VERSION 5.7 ;
  NOWIREEXTENSIONATPIN ON ;
  DIVIDERCHAR "/" ;
  BUSBITCHARS "[]" ;
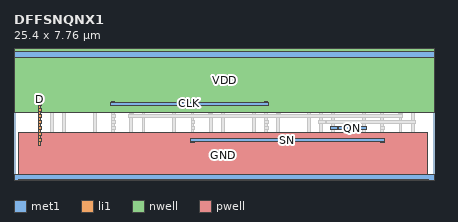
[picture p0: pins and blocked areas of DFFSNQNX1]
MACRO DFFSNQNX1
  CLASS CORE ;
  FOREIGN DFFSNQNX1 ;
  ORIGIN 0.000 0.000 ;
  SIZE 25.400 BY 7.760 ;
  SYMMETRY X Y ;
  SITE unitrh ;
  PIN QN
    DIRECTION OUTPUT ;
    USE SIGNAL ;
    ANTENNAGATEAREA 1.033250 ;
    PORT
      LAYER met1 ;
        RECT 21.040 3.225 21.270 3.255 ;
        RECT 19.625 3.055 21.300 3.225 ;
        RECT 21.040 3.025 21.270 3.055 ;
    END
    PORT
      LAYER met1 ;
        RECT 19.190 3.225 19.420 3.255 ;
        RECT 19.160 3.055 19.570 3.225 ;
        RECT 19.190 3.025 19.420 3.055 ;
    END
  END QN
  PIN D
    DIRECTION INPUT ;
    USE SIGNAL ;
    ANTENNAGATEAREA 1.033250 ;
    PORT
      LAYER li1 ;
        RECT 1.460 4.705 1.630 5.045 ;
        RECT 1.460 4.535 1.685 4.705 ;
        RECT 1.460 4.335 1.630 4.535 ;
        RECT 1.460 4.165 1.685 4.335 ;
        RECT 1.460 3.965 1.630 4.165 ;
        RECT 1.460 3.795 1.685 3.965 ;
        RECT 1.460 3.595 1.630 3.795 ;
        RECT 1.460 3.425 1.685 3.595 ;
        RECT 1.460 3.225 1.630 3.425 ;
        RECT 1.460 3.055 1.685 3.225 ;
        RECT 1.460 2.855 1.630 3.055 ;
        RECT 1.460 2.685 1.685 2.855 ;
        RECT 1.460 2.485 1.630 2.685 ;
        RECT 1.460 2.315 1.685 2.485 ;
        RECT 1.460 2.095 1.630 2.315 ;
    END
  END D
  PIN CLK
    DIRECTION INPUT ;
    USE SIGNAL ;
    ANTENNAGATEAREA 2.042100 ;
    PORT
      LAYER met1 ;
        RECT 5.870 4.705 6.100 4.735 ;
        RECT 15.120 4.705 15.350 4.735 ;
        RECT 5.840 4.535 15.380 4.705 ;
        RECT 5.870 4.505 6.100 4.535 ;
        RECT 15.120 4.505 15.350 4.535 ;
    END
  END CLK
  PIN SN
    DIRECTION INPUT ;
    USE SIGNAL ;
    ANTENNAGATEAREA 2.029700 ;
    PORT
      LAYER met1 ;
        RECT 10.680 2.485 10.910 2.515 ;
        RECT 22.150 2.485 22.380 2.515 ;
        RECT 10.650 2.315 22.410 2.485 ;
        RECT 10.680 2.285 10.910 2.315 ;
        RECT 22.150 2.285 22.380 2.315 ;
    END
  END SN
  PIN VDD
    DIRECTION INOUT ;
    USE POWER ;
    SHAPE ABUTMENT ;
    PORT
      LAYER nwell ;
        RECT 0.000 4.110 25.400 7.940 ;
      LAYER met1 ;
        RECT 0.000 7.410 25.400 7.760 ;
    END
  END VDD
  PIN GND
    DIRECTION INOUT ;
    USE GROUND ;
    SHAPE ABUTMENT ;
    PORT
      LAYER pwell ;
        RECT 0.265 0.060 25.025 2.900 ;
        RECT 0.265 0.010 25.080 0.060 ;
        RECT 0.320 0.000 25.080 0.010 ;
      LAYER met1 ;
        RECT 0.000 0.000 25.400 0.350 ;
    END
  END GND
  OBS
      LAYER li1 ;
        RECT 0.000 7.410 25.400 7.760 ;
        RECT 0.265 4.290 0.605 7.410 ;
        RECT 1.140 5.315 1.310 7.410 ;
        RECT 1.580 5.465 1.750 7.200 ;
        RECT 2.020 5.735 2.190 7.410 ;
        RECT 2.460 5.465 2.630 7.200 ;
        RECT 2.900 5.735 3.070 7.410 ;
        RECT 1.580 5.295 3.110 5.465 ;
        RECT 2.230 4.890 2.400 5.045 ;
        RECT 2.200 4.715 2.400 4.890 ;
        RECT 0.265 0.350 0.605 2.900 ;
        RECT 2.200 2.095 2.370 4.715 ;
        RECT 1.045 1.845 1.215 1.925 ;
        RECT 2.015 1.845 2.185 1.925 ;
        RECT 2.940 1.920 3.110 5.295 ;
        RECT 3.595 4.290 3.935 7.410 ;
        RECT 4.770 5.395 4.940 7.410 ;
        RECT 5.210 5.420 5.380 7.200 ;
        RECT 5.650 5.735 5.820 7.410 ;
        RECT 6.090 5.420 6.260 7.200 ;
        RECT 6.530 5.735 6.700 7.410 ;
        RECT 6.970 5.420 7.140 7.200 ;
        RECT 7.410 5.735 7.580 7.410 ;
        RECT 5.210 5.250 7.920 5.420 ;
        RECT 1.045 1.675 2.185 1.845 ;
        RECT 1.045 0.545 1.215 1.675 ;
        RECT 1.530 0.350 1.700 1.300 ;
        RECT 2.015 0.795 2.185 1.675 ;
        RECT 2.500 1.750 3.110 1.920 ;
        RECT 2.500 1.015 2.670 1.750 ;
        RECT 2.985 0.795 3.155 1.565 ;
        RECT 2.015 0.625 3.155 0.795 ;
        RECT 2.015 0.545 2.185 0.625 ;
        RECT 2.985 0.545 3.155 0.625 ;
        RECT 3.595 0.350 3.935 2.900 ;
        RECT 4.790 2.095 4.960 5.045 ;
        RECT 5.900 4.705 6.070 5.045 ;
        RECT 5.900 4.535 6.125 4.705 ;
        RECT 5.900 3.965 6.070 4.535 ;
        RECT 5.900 3.795 6.125 3.965 ;
        RECT 5.900 3.595 6.070 3.795 ;
        RECT 5.900 3.425 6.125 3.595 ;
        RECT 5.900 3.225 6.070 3.425 ;
        RECT 5.900 3.055 6.125 3.225 ;
        RECT 5.900 2.095 6.070 3.055 ;
        RECT 7.010 2.095 7.180 5.045 ;
        RECT 7.750 4.415 7.920 5.250 ;
        RECT 7.745 4.085 7.920 4.415 ;
        RECT 8.405 4.290 8.745 7.410 ;
        RECT 9.580 5.395 9.750 7.410 ;
        RECT 10.020 5.420 10.190 7.200 ;
        RECT 10.460 5.735 10.630 7.410 ;
        RECT 10.900 5.420 11.070 7.200 ;
        RECT 11.340 5.735 11.510 7.410 ;
        RECT 11.780 5.420 11.950 7.200 ;
        RECT 12.220 5.735 12.390 7.410 ;
        RECT 10.020 5.250 12.730 5.420 ;
        RECT 4.270 1.855 4.440 1.935 ;
        RECT 5.240 1.855 5.410 1.935 ;
        RECT 6.210 1.855 6.380 1.935 ;
        RECT 4.270 1.685 6.380 1.855 ;
        RECT 4.270 0.555 4.440 1.685 ;
        RECT 4.755 0.350 4.925 1.310 ;
        RECT 5.240 0.805 5.410 1.685 ;
        RECT 6.210 1.605 6.380 1.685 ;
        RECT 5.730 1.260 5.900 1.340 ;
        RECT 6.780 1.260 6.950 1.935 ;
        RECT 7.750 1.930 7.920 4.085 ;
        RECT 5.730 1.090 6.950 1.260 ;
        RECT 5.730 1.010 5.900 1.090 ;
        RECT 6.210 0.805 6.380 0.885 ;
        RECT 5.240 0.635 6.380 0.805 ;
        RECT 5.240 0.555 5.410 0.635 ;
        RECT 6.210 0.555 6.380 0.635 ;
        RECT 6.780 0.805 6.950 1.090 ;
        RECT 7.265 1.760 7.920 1.930 ;
        RECT 7.265 1.025 7.435 1.760 ;
        RECT 7.750 0.805 7.920 1.575 ;
        RECT 6.780 0.635 7.920 0.805 ;
        RECT 6.780 0.555 6.950 0.635 ;
        RECT 7.750 0.555 7.920 0.635 ;
        RECT 8.405 0.350 8.745 2.900 ;
        RECT 9.600 2.095 9.770 5.045 ;
        RECT 10.710 3.595 10.880 5.045 ;
        RECT 10.710 3.425 10.935 3.595 ;
        RECT 10.710 3.225 10.880 3.425 ;
        RECT 10.710 3.055 10.935 3.225 ;
        RECT 10.710 2.855 10.880 3.055 ;
        RECT 10.710 2.685 10.935 2.855 ;
        RECT 10.710 2.485 10.880 2.685 ;
        RECT 10.710 2.315 10.935 2.485 ;
        RECT 10.710 2.095 10.880 2.315 ;
        RECT 11.820 2.095 11.990 5.045 ;
        RECT 9.080 1.855 9.250 1.935 ;
        RECT 10.050 1.855 10.220 1.935 ;
        RECT 11.020 1.855 11.190 1.935 ;
        RECT 9.080 1.685 11.190 1.855 ;
        RECT 9.080 0.555 9.250 1.685 ;
        RECT 9.565 0.350 9.735 1.310 ;
        RECT 10.050 0.805 10.220 1.685 ;
        RECT 11.020 1.605 11.190 1.685 ;
        RECT 10.540 1.260 10.710 1.340 ;
        RECT 11.590 1.260 11.760 1.935 ;
        RECT 12.560 1.930 12.730 5.250 ;
        RECT 13.215 4.290 13.555 7.410 ;
        RECT 14.090 5.315 14.260 7.410 ;
        RECT 14.530 5.465 14.700 7.200 ;
        RECT 14.970 5.735 15.140 7.410 ;
        RECT 15.410 5.465 15.580 7.200 ;
        RECT 15.850 5.735 16.020 7.410 ;
        RECT 14.530 5.295 16.060 5.465 ;
        RECT 10.540 1.090 11.760 1.260 ;
        RECT 10.540 1.010 10.710 1.090 ;
        RECT 11.020 0.805 11.190 0.885 ;
        RECT 10.050 0.635 11.190 0.805 ;
        RECT 10.050 0.555 10.220 0.635 ;
        RECT 11.020 0.555 11.190 0.635 ;
        RECT 11.590 0.805 11.760 1.090 ;
        RECT 12.075 1.760 12.730 1.930 ;
        RECT 12.075 1.025 12.245 1.760 ;
        RECT 12.560 0.805 12.730 1.575 ;
        RECT 11.590 0.635 12.730 0.805 ;
        RECT 11.590 0.555 11.760 0.635 ;
        RECT 12.560 0.555 12.730 0.635 ;
        RECT 13.215 0.350 13.555 2.900 ;
        RECT 14.410 2.095 14.580 5.045 ;
        RECT 15.180 4.890 15.350 5.045 ;
        RECT 15.150 4.715 15.350 4.890 ;
        RECT 15.150 4.705 15.320 4.715 ;
        RECT 15.150 4.535 15.375 4.705 ;
        RECT 15.150 3.595 15.320 4.535 ;
        RECT 15.150 3.425 15.375 3.595 ;
        RECT 15.150 3.225 15.320 3.425 ;
        RECT 15.150 3.055 15.375 3.225 ;
        RECT 15.150 2.855 15.320 3.055 ;
        RECT 15.150 2.685 15.375 2.855 ;
        RECT 15.150 2.095 15.320 2.685 ;
        RECT 13.995 1.845 14.165 1.925 ;
        RECT 14.965 1.845 15.135 1.925 ;
        RECT 15.890 1.920 16.060 5.295 ;
        RECT 16.545 4.290 16.885 7.410 ;
        RECT 17.420 5.315 17.590 7.410 ;
        RECT 17.860 5.465 18.030 7.200 ;
        RECT 18.300 5.735 18.470 7.410 ;
        RECT 18.740 5.465 18.910 7.200 ;
        RECT 19.180 5.735 19.350 7.410 ;
        RECT 17.860 5.295 19.390 5.465 ;
        RECT 19.220 5.075 19.390 5.295 ;
        RECT 13.995 1.675 15.135 1.845 ;
        RECT 13.995 0.545 14.165 1.675 ;
        RECT 14.480 0.350 14.650 1.300 ;
        RECT 14.965 0.795 15.135 1.675 ;
        RECT 15.450 1.750 16.060 1.920 ;
        RECT 15.450 1.015 15.620 1.750 ;
        RECT 15.935 0.795 16.105 1.565 ;
        RECT 14.965 0.625 16.105 0.795 ;
        RECT 14.965 0.545 15.135 0.625 ;
        RECT 15.935 0.545 16.105 0.625 ;
        RECT 16.545 0.350 16.885 2.900 ;
        RECT 17.740 2.095 17.910 5.045 ;
        RECT 18.510 4.890 18.680 5.045 ;
        RECT 18.480 4.715 18.680 4.890 ;
        RECT 19.220 4.905 19.445 5.075 ;
        RECT 18.480 2.095 18.650 4.715 ;
        RECT 19.220 4.705 19.390 4.905 ;
        RECT 19.220 4.535 19.445 4.705 ;
        RECT 19.220 4.335 19.390 4.535 ;
        RECT 19.220 4.165 19.445 4.335 ;
        RECT 19.875 4.290 20.215 7.410 ;
        RECT 21.050 5.395 21.220 7.410 ;
        RECT 21.490 5.420 21.660 7.200 ;
        RECT 21.930 5.735 22.100 7.410 ;
        RECT 22.370 5.420 22.540 7.200 ;
        RECT 22.810 5.735 22.980 7.410 ;
        RECT 23.250 5.420 23.420 7.200 ;
        RECT 23.690 5.735 23.860 7.410 ;
        RECT 21.490 5.250 24.200 5.420 ;
        RECT 21.070 4.705 21.240 5.045 ;
        RECT 22.180 4.705 22.350 5.045 ;
        RECT 21.070 4.535 21.295 4.705 ;
        RECT 22.180 4.535 22.405 4.705 ;
        RECT 21.070 4.335 21.240 4.535 ;
        RECT 22.180 4.335 22.350 4.535 ;
        RECT 21.070 4.165 21.295 4.335 ;
        RECT 22.180 4.165 22.405 4.335 ;
        RECT 19.220 3.225 19.390 4.165 ;
        RECT 21.070 3.225 21.240 4.165 ;
        RECT 22.180 3.225 22.350 4.165 ;
        RECT 19.220 3.055 19.445 3.225 ;
        RECT 21.070 3.055 21.295 3.225 ;
        RECT 22.180 3.055 22.405 3.225 ;
        RECT 19.220 2.855 19.390 3.055 ;
        RECT 19.220 2.685 19.445 2.855 ;
        RECT 17.325 1.845 17.495 1.925 ;
        RECT 18.295 1.845 18.465 1.925 ;
        RECT 19.220 1.920 19.390 2.685 ;
        RECT 17.325 1.675 18.465 1.845 ;
        RECT 17.325 0.545 17.495 1.675 ;
        RECT 17.810 0.350 17.980 1.300 ;
        RECT 18.295 0.795 18.465 1.675 ;
        RECT 18.780 1.750 19.390 1.920 ;
        RECT 18.780 1.015 18.950 1.750 ;
        RECT 19.265 0.795 19.435 1.565 ;
        RECT 18.295 0.625 19.435 0.795 ;
        RECT 18.295 0.545 18.465 0.625 ;
        RECT 19.265 0.545 19.435 0.625 ;
        RECT 19.875 0.350 20.215 2.900 ;
        RECT 21.070 2.855 21.240 3.055 ;
        RECT 22.180 2.855 22.350 3.055 ;
        RECT 21.070 2.685 21.295 2.855 ;
        RECT 22.180 2.685 22.405 2.855 ;
        RECT 21.070 2.095 21.240 2.685 ;
        RECT 22.180 2.485 22.350 2.685 ;
        RECT 22.180 2.315 22.405 2.485 ;
        RECT 22.180 2.095 22.350 2.315 ;
        RECT 23.290 2.095 23.460 5.045 ;
        RECT 20.550 1.855 20.720 1.935 ;
        RECT 21.520 1.855 21.690 1.935 ;
        RECT 22.490 1.855 22.660 1.935 ;
        RECT 20.550 1.685 22.660 1.855 ;
        RECT 20.550 0.555 20.720 1.685 ;
        RECT 21.035 0.350 21.205 1.310 ;
        RECT 21.520 0.805 21.690 1.685 ;
        RECT 22.490 1.605 22.660 1.685 ;
        RECT 22.010 1.260 22.180 1.340 ;
        RECT 23.060 1.260 23.230 1.935 ;
        RECT 24.030 1.930 24.200 5.250 ;
        RECT 24.685 4.290 25.025 7.410 ;
        RECT 22.010 1.090 23.230 1.260 ;
        RECT 22.010 1.010 22.180 1.090 ;
        RECT 22.490 0.805 22.660 0.885 ;
        RECT 21.520 0.635 22.660 0.805 ;
        RECT 21.520 0.555 21.690 0.635 ;
        RECT 22.490 0.555 22.660 0.635 ;
        RECT 23.060 0.805 23.230 1.090 ;
        RECT 23.545 1.760 24.200 1.930 ;
        RECT 23.545 1.025 23.715 1.760 ;
        RECT 24.030 0.805 24.200 1.575 ;
        RECT 23.060 0.635 24.200 0.805 ;
        RECT 23.060 0.555 23.230 0.635 ;
        RECT 24.030 0.555 24.200 0.635 ;
        RECT 24.685 0.350 25.025 2.900 ;
        RECT 0.000 0.000 25.400 0.350 ;
      LAYER mcon ;
        RECT 0.720 7.495 0.890 7.665 ;
        RECT 1.090 7.495 1.260 7.665 ;
        RECT 1.460 7.495 1.630 7.665 ;
        RECT 1.830 7.495 2.000 7.665 ;
        RECT 2.200 7.495 2.370 7.665 ;
        RECT 2.570 7.495 2.740 7.665 ;
        RECT 2.940 7.495 3.110 7.665 ;
        RECT 3.310 7.495 3.480 7.665 ;
        RECT 4.050 7.495 4.220 7.665 ;
        RECT 4.420 7.495 4.590 7.665 ;
        RECT 4.790 7.495 4.960 7.665 ;
        RECT 5.160 7.495 5.330 7.665 ;
        RECT 5.530 7.495 5.700 7.665 ;
        RECT 5.900 7.495 6.070 7.665 ;
        RECT 6.270 7.495 6.440 7.665 ;
        RECT 6.640 7.495 6.810 7.665 ;
        RECT 7.010 7.495 7.180 7.665 ;
        RECT 7.380 7.495 7.550 7.665 ;
        RECT 7.750 7.495 7.920 7.665 ;
        RECT 8.120 7.495 8.290 7.665 ;
        RECT 8.860 7.495 9.030 7.665 ;
        RECT 9.230 7.495 9.400 7.665 ;
        RECT 9.600 7.495 9.770 7.665 ;
        RECT 9.970 7.495 10.140 7.665 ;
        RECT 10.340 7.495 10.510 7.665 ;
        RECT 10.710 7.495 10.880 7.665 ;
        RECT 11.080 7.495 11.250 7.665 ;
        RECT 11.450 7.495 11.620 7.665 ;
        RECT 11.820 7.495 11.990 7.665 ;
        RECT 12.190 7.495 12.360 7.665 ;
        RECT 12.560 7.495 12.730 7.665 ;
        RECT 12.930 7.495 13.100 7.665 ;
        RECT 13.670 7.495 13.840 7.665 ;
        RECT 14.040 7.495 14.210 7.665 ;
        RECT 14.410 7.495 14.580 7.665 ;
        RECT 14.780 7.495 14.950 7.665 ;
        RECT 15.150 7.495 15.320 7.665 ;
        RECT 15.520 7.495 15.690 7.665 ;
        RECT 15.890 7.495 16.060 7.665 ;
        RECT 16.260 7.495 16.430 7.665 ;
        RECT 17.000 7.495 17.170 7.665 ;
        RECT 17.370 7.495 17.540 7.665 ;
        RECT 17.740 7.495 17.910 7.665 ;
        RECT 18.110 7.495 18.280 7.665 ;
        RECT 18.480 7.495 18.650 7.665 ;
        RECT 18.850 7.495 19.020 7.665 ;
        RECT 19.220 7.495 19.390 7.665 ;
        RECT 19.590 7.495 19.760 7.665 ;
        RECT 20.330 7.495 20.500 7.665 ;
        RECT 20.700 7.495 20.870 7.665 ;
        RECT 21.070 7.495 21.240 7.665 ;
        RECT 21.440 7.495 21.610 7.665 ;
        RECT 21.810 7.495 21.980 7.665 ;
        RECT 22.180 7.495 22.350 7.665 ;
        RECT 22.550 7.495 22.720 7.665 ;
        RECT 22.920 7.495 23.090 7.665 ;
        RECT 23.290 7.495 23.460 7.665 ;
        RECT 23.660 7.495 23.830 7.665 ;
        RECT 24.030 7.495 24.200 7.665 ;
        RECT 24.400 7.495 24.570 7.665 ;
        RECT 2.200 4.165 2.370 4.335 ;
        RECT 2.940 2.685 3.110 2.855 ;
        RECT 4.790 2.680 4.960 2.850 ;
        RECT 7.745 4.165 7.915 4.335 ;
        RECT 7.010 3.795 7.180 3.965 ;
        RECT 9.600 2.685 9.770 2.855 ;
        RECT 11.820 3.795 11.990 3.965 ;
        RECT 12.560 2.685 12.730 2.855 ;
        RECT 14.410 2.685 14.580 2.855 ;
        RECT 15.890 3.795 16.060 3.965 ;
        RECT 17.740 4.165 17.910 4.335 ;
        RECT 18.480 3.425 18.650 3.595 ;
        RECT 23.290 3.795 23.460 3.965 ;
        RECT 24.030 3.425 24.200 3.595 ;
        RECT 0.720 0.095 0.890 0.265 ;
        RECT 1.090 0.095 1.260 0.265 ;
        RECT 1.460 0.095 1.630 0.265 ;
        RECT 1.830 0.095 2.000 0.265 ;
        RECT 2.200 0.095 2.370 0.265 ;
        RECT 2.570 0.095 2.740 0.265 ;
        RECT 2.940 0.095 3.110 0.265 ;
        RECT 3.310 0.095 3.480 0.265 ;
        RECT 4.050 0.095 4.220 0.265 ;
        RECT 4.420 0.095 4.590 0.265 ;
        RECT 4.790 0.095 4.960 0.265 ;
        RECT 5.160 0.095 5.330 0.265 ;
        RECT 5.530 0.095 5.700 0.265 ;
        RECT 5.900 0.095 6.070 0.265 ;
        RECT 6.270 0.095 6.440 0.265 ;
        RECT 6.640 0.095 6.810 0.265 ;
        RECT 7.010 0.095 7.180 0.265 ;
        RECT 7.380 0.095 7.550 0.265 ;
        RECT 7.750 0.095 7.920 0.265 ;
        RECT 8.120 0.095 8.290 0.265 ;
        RECT 8.860 0.095 9.030 0.265 ;
        RECT 9.230 0.095 9.400 0.265 ;
        RECT 9.600 0.095 9.770 0.265 ;
        RECT 9.970 0.095 10.140 0.265 ;
        RECT 10.340 0.095 10.510 0.265 ;
        RECT 10.710 0.095 10.880 0.265 ;
        RECT 11.080 0.095 11.250 0.265 ;
        RECT 11.450 0.095 11.620 0.265 ;
        RECT 11.820 0.095 11.990 0.265 ;
        RECT 12.190 0.095 12.360 0.265 ;
        RECT 12.560 0.095 12.730 0.265 ;
        RECT 12.930 0.095 13.100 0.265 ;
        RECT 13.670 0.095 13.840 0.265 ;
        RECT 14.040 0.095 14.210 0.265 ;
        RECT 14.410 0.095 14.580 0.265 ;
        RECT 14.780 0.095 14.950 0.265 ;
        RECT 15.150 0.095 15.320 0.265 ;
        RECT 15.520 0.095 15.690 0.265 ;
        RECT 15.890 0.095 16.060 0.265 ;
        RECT 16.260 0.095 16.430 0.265 ;
        RECT 17.000 0.095 17.170 0.265 ;
        RECT 17.370 0.095 17.540 0.265 ;
        RECT 17.740 0.095 17.910 0.265 ;
        RECT 18.110 0.095 18.280 0.265 ;
        RECT 18.480 0.095 18.650 0.265 ;
        RECT 18.850 0.095 19.020 0.265 ;
        RECT 19.220 0.095 19.390 0.265 ;
        RECT 19.590 0.095 19.760 0.265 ;
        RECT 20.330 0.095 20.500 0.265 ;
        RECT 20.700 0.095 20.870 0.265 ;
        RECT 21.070 0.095 21.240 0.265 ;
        RECT 21.440 0.095 21.610 0.265 ;
        RECT 21.810 0.095 21.980 0.265 ;
        RECT 22.180 0.095 22.350 0.265 ;
        RECT 22.550 0.095 22.720 0.265 ;
        RECT 22.920 0.095 23.090 0.265 ;
        RECT 23.290 0.095 23.460 0.265 ;
        RECT 23.660 0.095 23.830 0.265 ;
        RECT 24.030 0.095 24.200 0.265 ;
        RECT 24.400 0.095 24.570 0.265 ;
      LAYER met1 ;
        RECT 2.170 4.335 2.400 4.365 ;
        RECT 7.715 4.335 7.945 4.365 ;
        RECT 17.710 4.335 17.940 4.365 ;
        RECT 2.140 4.165 17.970 4.335 ;
        RECT 2.170 4.135 2.400 4.165 ;
        RECT 7.715 4.135 7.945 4.165 ;
        RECT 17.710 4.135 17.940 4.165 ;
        RECT 6.980 3.965 7.210 3.995 ;
        RECT 11.790 3.965 12.020 3.995 ;
        RECT 15.860 3.965 16.090 3.995 ;
        RECT 23.260 3.965 23.490 3.995 ;
        RECT 6.950 3.795 23.520 3.965 ;
        RECT 6.980 3.765 7.210 3.795 ;
        RECT 11.790 3.765 12.020 3.795 ;
        RECT 15.860 3.765 16.090 3.795 ;
        RECT 23.260 3.765 23.490 3.795 ;
        RECT 18.450 3.595 18.680 3.625 ;
        RECT 24.000 3.595 24.230 3.625 ;
        RECT 18.420 3.425 18.830 3.595 ;
        RECT 18.885 3.425 24.260 3.595 ;
        RECT 18.450 3.395 18.680 3.425 ;
        RECT 24.000 3.395 24.230 3.425 ;
        RECT 2.910 2.855 3.140 2.885 ;
        RECT 4.760 2.855 4.990 2.880 ;
        RECT 9.570 2.855 9.800 2.885 ;
        RECT 12.530 2.855 12.760 2.885 ;
        RECT 14.380 2.855 14.610 2.885 ;
        RECT 2.880 2.685 9.830 2.855 ;
        RECT 12.500 2.685 14.640 2.855 ;
        RECT 2.910 2.655 3.140 2.685 ;
        RECT 4.730 2.680 5.140 2.685 ;
        RECT 4.760 2.650 4.990 2.680 ;
        RECT 9.570 2.655 9.800 2.685 ;
        RECT 12.530 2.655 12.760 2.685 ;
        RECT 14.380 2.655 14.610 2.685 ;
  END
END DFFSNQNX1
END LIBRARY

